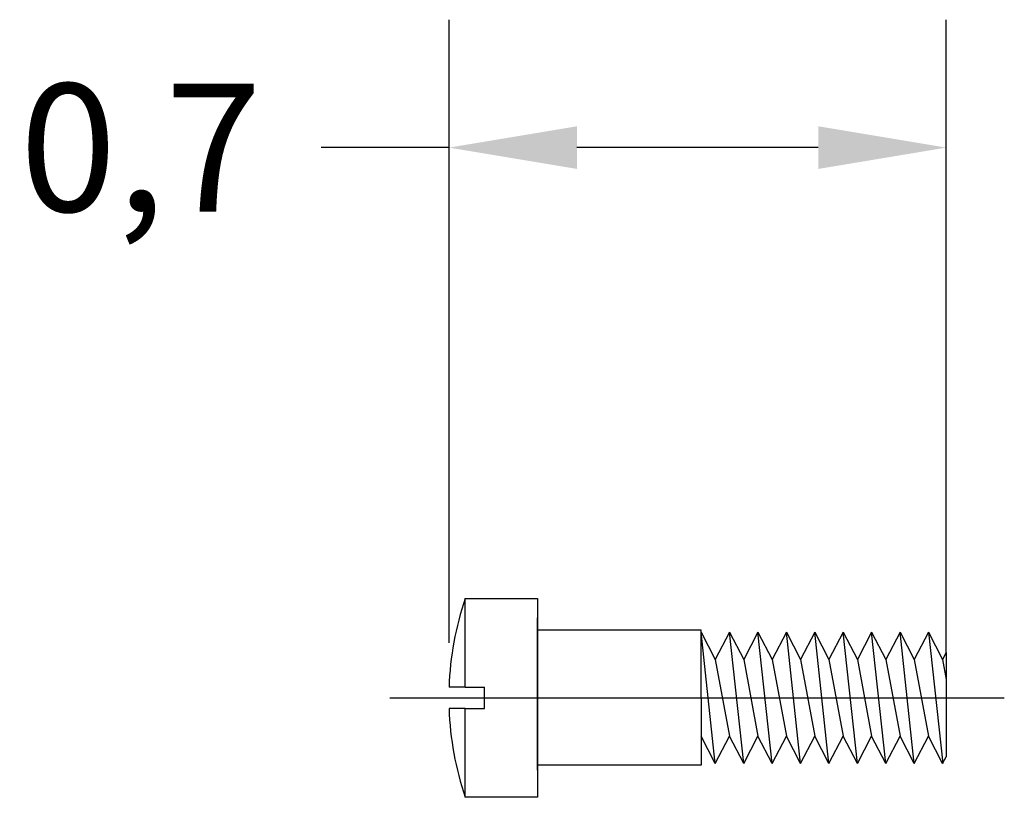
# Model space of a CAD drawing. Units: millimetres. Extents: x -0.96 to 0.43, y -0.14 to 0.95.
import ezdxf

# ---------------------------------------------------------------- set-up
doc = ezdxf.new("R2010")
doc.units = ezdxf.units.MM
doc.styles.get("Standard").update_dxf_attribs({"font": 'ARIAL.TTF'})
doc.dimstyles.get("Standard").update_dxf_attribs({"dimtxt": 0.18, "dimasz": 0.18, "dimexe": 0.18, "dimexo": 0.0625, "dimgap": 0.09, "dimtad": 0, "dimtih": 1, "dimtoh": 1, "dimdec": 4, "dimzin": 0, "dimdsep": 46, "dimtxsty": 'Standard', "dimcen": 0.09, "dimadec": 0, "dimazin": 0, "dimtfac": 1, "dimtdec": 4, "dimtofl": 0, "dimtmove": 0, "dimatfit": 3, "dimfxl": 0, "dimtolj": 1, "dimtzin": 0, "dimarcsym": 0})

# ---------------------------------------------------------------- blocks, each defined once
blk = doc.blocks.new('*D2')
at = {"color": 0, "lineweight": -2}
for p, q in [((-0.3547, 0.0775), (-0.3547, 0.9543)), ((0.345, 0.0625), (0.345, 0.9543)), ((-0.3547, 0.7743), (-0.5347, 0.7743)), ((0.165, 0.7743), (-0.1747, 0.7743))]:
    blk.add_line(p, q, dxfattribs=at)
at = {"color": 0}
for points in [[(-0.1747, 0.8043), (-0.1747, 0.7443), (-0.3547, 0.7743)], [(0.165, 0.8043), (0.165, 0.7443), (0.345, 0.7743)]]:
    blk.add_solid(points, dxfattribs=at)
at = {"layer": 'Defpoints', "color": 0}
for p in [(-0.3547, 0.7743), (-0.3547, 0.015), (0.345, 0)]:
    blk.add_point(p, dxfattribs=at)
at = {"color": 0, "insert": (-0.7886, 0.7743), "char_height": 0.18, "attachment_point": 5}
blk.add_mtext('\\A1;0,7', dxfattribs=at)

msp = doc.modelspace()

# ---------------------------------------------------------------- linework, layer by layer
for p, q in [((-0.332, 0.14), (-0.23, 0.14)), ((-0.332, 0.015), (-0.332, 0.14)), ((-0.23, 0.14), (-0.23, 0)), ((-0.23, -0.10189), (-0.23, 0.1127)), ((0, 0.095), (-0.23, 0.095)), ((0, 0), (0, 0.095)), ((0, 0.0925), (0.02, 0.05408)), ((0.02, -0.0925), (0, 0.0925)), ((0.04, 0.0925), (0.02, 0.05408)), ((0.04, 0.0925), (0.06, 0.05408)), ((0.06, -0.0925), (0.04, 0.0925)), ((0.08, 0.0925), (0.06, 0.05408)), ((0.08, 0.0925), (0.1, 0.05408)), ((0.1, -0.0925), (0.08, 0.0925)), ((0.12, 0.0925), (0.1, 0.05408)), ((0.12, 0.0925), (0.14, 0.05408)), ((0.14, -0.0925), (0.12, 0.0925)), ((0.16, 0.0925), (0.14, 0.05408)), ((0.16, 0.0925), (0.18, 0.05408)), ((0.18, -0.0925), (0.16, 0.0925)), ((0.2, 0.0925), (0.18, 0.05408)), ((0.2, 0.0925), (0.22, 0.05408)), ((0.22, -0.0925), (0.2, 0.0925)), ((0.24, 0.0925), (0.22, 0.05408)), ((0.24, 0.0925), (0.26, 0.05408)), ((0.26, -0.0925), (0.24, 0.0925)), ((0.28, 0.0925), (0.26, 0.05408)), ((0.28, 0.0925), (0.3, 0.05408)), ((0.3, -0.0925), (0.28, 0.0925)), ((0.32, 0.0925), (0.3, 0.05408)), ((0.32, 0.0925), (0.34, 0.05408)), ((0.32, 0.0925), (0.34007, -0.09237)), ((0.345, 0.06369), (0.34, 0.05408)), ((0.345, 0.06369), (0.345, -0.0829)), ((0.02, 0.05408), (0.04, -0.05408)), ((0.06, 0.05408), (0.08, -0.05408)), ((0.1, 0.05408), (0.12, -0.05408)), ((0.14, 0.05408), (0.16, -0.05408)), ((0.18, 0.05408), (0.2, -0.05408)), ((0.22, 0.05408), (0.24, -0.05408)), ((0.26, 0.05408), (0.28, -0.05408)), ((0.3, 0.05408), (0.32, -0.05408)), ((0.34, 0.05408), (0.345, 0.02579)), ((-0.332, 0.015), (-0.35474, 0.015)), ((-0.332, 0.015), (-0.305, 0.015)), ((-0.305, -0.015), (-0.305, 0.015)), ((-0.23, 0), (-0.23, -0.10189)), ((-0.23, 0), (-0.23, -0.14)), ((0, 0), (0, -0.095)), ((-0.332, -0.015), (-0.35474, -0.015)), ((-0.332, -0.14), (-0.332, -0.015)), ((-0.332, -0.015), (-0.305, -0.015)), ((0.02, -0.0925), (0, -0.05408)), ((0.02, -0.0925), (0.04, -0.05408)), ((0.06, -0.0925), (0.04, -0.05408)), ((0.06, -0.0925), (0.08, -0.05408)), ((0.1, -0.0925), (0.08, -0.05408)), ((0.1, -0.0925), (0.12, -0.05408)), ((0.14, -0.0925), (0.12, -0.05408)), ((0.14, -0.0925), (0.16, -0.05408)), ((0.18, -0.0925), (0.16, -0.05408)), ((0.18, -0.0925), (0.2, -0.05408)), ((0.22, -0.0925), (0.2, -0.05408)), ((0.22, -0.0925), (0.24, -0.05408)), ((0.26, -0.0925), (0.24, -0.05408)), ((0.26, -0.0925), (0.28, -0.05408)), ((0.3, -0.0925), (0.28, -0.05408)), ((0.3, -0.0925), (0.32, -0.05408)), ((0.34, -0.0925), (0.32, -0.05408)), ((0.34, -0.0925), (0.345, -0.0829)), ((0, -0.095), (-0.23, -0.095)), ((-0.23, -0.14), (-0.332, -0.14))]:
    msp.add_line(p, q)
at = {"color": 1}
msp.add_line((-0.43787, 0), (0.42677, 0), dxfattribs=at)
for start, end in [(161.34092, 178.03558), (181.96442, 198.65908)]:
    msp.add_arc((0.08259, 0), 0.43759, start, end)

# ---------------------------------------------------------------- dimensions: what is measured, and where the dimension line sits
dim = msp.add_linear_dim(base=(-0.35474, 0.77431), p1=(0.345, 0), p2=(-0.35474, 0.015), text='0,7', dimstyle='Standard')
dim.commit()
dim.dimension.update_dxf_attribs({"geometry": '*D2', "text_midpoint": (-0.7886, 0.77431)})

doc.saveas('drawing.dxf')
